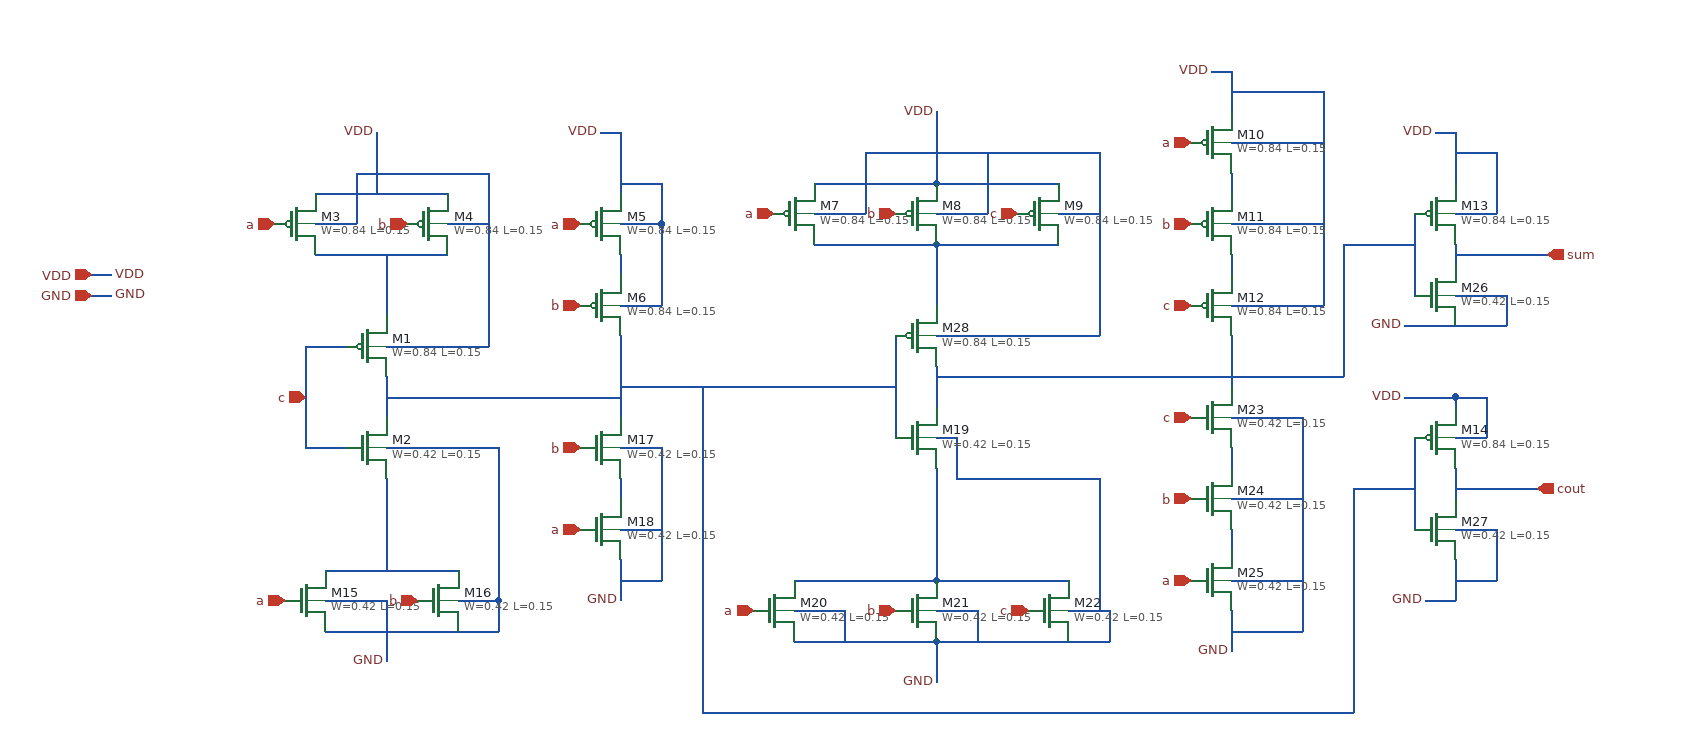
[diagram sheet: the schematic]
v {xschem version=3.4.3 file_version=1.2
}
G {}
K {}
V {}
S {}
E {}
N 210 -180 210 -140 {
lab=#net1}
N 130 -210 170 -210 {
lab=#net2}
N 130 -210 130 -110 {
lab=#net2}
N 130 -110 170 -110 {
lab=#net2}
N 210 -80 210 -60 {
lab=#net3}
N 210 -210 230 -210 {
lab=VDD}
N 210 -110 230 -110 {
lab=GND}
N 210 -60 210 -20 {
lab=#net3}
N -80 -280 -60 -280 {
lab=VDD}
N -80 -260 -60 -260 {
lab=GND}
N 140 -360 140 -350 {
lab=VDD}
N 140 -360 270 -360 {
lab=VDD}
N 200 -420 200 -360 {
lab=VDD}
N 420 -420 440 -420 {
lab=VDD}
N 440 -420 440 -360 {
lab=VDD}
N 750 -440 750 -370 {
lab=VDD}
N 630 -370 750 -370 {
lab=VDD}
N 750 -370 870 -370 {
lab=VDD}
N 1020 -480 1040 -480 {
lab=VDD}
N 1040 -480 1040 -440 {
lab=VDD}
N 1240 -420 1260 -420 {
lab=VDD}
N 1260 -420 1260 -370 {
lab=VDD}
N 1260 -310 1260 -290 {
lab=sum}
N 1040 -380 1040 -360 {
lab=#net4}
N 1040 -300 1040 -280 {
lab=#net5}
N 1260 -90 1260 -60 {
lab=cout}
N 1220 -120 1220 -30 {
lab=#net6}
N 1220 -340 1220 -260 {
lab=#net7}
N 1210 -230 1260 -230 {
lab=GND}
N 1260 -160 1260 -150 {
lab=VDD}
N 1210 -160 1260 -160 {
lab=VDD}
N 1260 0 1260 40 {
lab=GND}
N 1230 40 1260 40 {
lab=GND}
N 1040 -30 1040 -10 {
lab=#net8}
N 1040 -110 1040 -90 {
lab=#net9}
N 1040 50 1040 90 {
lab=GND}
N 750 80 880 80 {
lab=GND}
N 610 80 750 80 {
lab=GND}
N 750 80 750 120 {
lab=GND}
N 620 20 750 20 {
lab=#net10}
N 610 20 620 20 {
lab=#net10}
N 760 20 880 20 {
lab=#net10}
N 750 20 760 20 {
lab=#net10}
N 750 -90 750 20 {
lab=#net10}
N 750 -190 750 -150 {
lab=#net11}
N 750 -310 750 -250 {
lab=#net12}
N 630 -310 750 -310 {
lab=#net12}
N 750 -310 870 -310 {
lab=#net12}
N 1040 -220 1040 -170 {
lab=#net13}
N 440 -80 440 -60 {
lab=#net14}
N 440 -220 440 -140 {
lab=#net15}
N 440 0 440 40 {
lab=GND}
N 440 -300 440 -280 {
lab=#net16}
N 150 10 280 10 {
lab=#net3}
N 150 70 280 70 {
lab=GND}
N 210 70 210 100 {
lab=GND}
N 210 -20 210 10 {
lab=#net3}
N 210 -250 210 -240 {
lab=#net17}
N 150 -300 270 -300 {
lab=#net17}
N 140 -300 150 -300 {
lab=#net17}
N 210 -300 210 -250 {
lab=#net17}
N 440 -330 480 -330 {
lab=VDD}
N 480 -370 480 -330 {
lab=VDD}
N 440 -370 480 -370 {
lab=VDD}
N 460 -250 480 -250 {
lab=VDD}
N 440 -250 460 -250 {
lab=VDD}
N 480 -280 480 -250 {
lab=VDD}
N 480 -330 480 -290 {
lab=VDD}
N 480 -290 480 -280 {
lab=VDD}
N 440 -110 480 -110 {
lab=GND}
N 480 -110 480 20 {
lab=GND}
N 440 20 480 20 {
lab=GND}
N 440 -30 480 -30 {
lab=GND}
N 150 40 210 40 {
lab=GND}
N 210 40 210 70 {
lab=GND}
N 280 40 320 40 {
lab=GND}
N 320 50 320 70 {
lab=GND}
N 280 70 320 70 {
lab=GND}
N 320 40 320 50 {
lab=GND}
N 610 50 660 50 {
lab=GND}
N 660 50 660 80 {
lab=GND}
N 750 50 790 50 {
lab=GND}
N 790 50 790 80 {
lab=GND}
N 880 50 920 50 {
lab=GND}
N 920 60 920 80 {
lab=GND}
N 880 80 920 80 {
lab=GND}
N 920 50 920 60 {
lab=GND}
N 750 -120 770 -120 {
lab=GND}
N 770 -120 770 -80 {
lab=GND}
N 750 -220 910 -220 {
lab=VDD}
N 910 -400 910 -220 {
lab=VDD}
N 750 -400 910 -400 {
lab=VDD}
N 770 -80 910 -80 {
lab=GND}
N 910 -80 910 50 {
lab=GND}
N 880 -340 910 -340 {
lab=VDD}
N 870 -340 880 -340 {
lab=VDD}
N 750 -340 800 -340 {
lab=VDD}
N 800 -400 800 -340 {
lab=VDD}
N 630 -340 680 -340 {
lab=VDD}
N 680 -400 680 -340 {
lab=VDD}
N 680 -400 750 -400 {
lab=VDD}
N 1040 -250 1130 -250 {
lab=VDD}
N 1130 -460 1130 -250 {
lab=VDD}
N 1040 -460 1130 -460 {
lab=VDD}
N 1040 -410 1130 -410 {
lab=VDD}
N 1040 -330 1130 -330 {
lab=VDD}
N 1040 -140 1110 -140 {
lab=GND}
N 1110 -140 1110 70 {
lab=GND}
N 1040 70 1110 70 {
lab=GND}
N 1040 20 1110 20 {
lab=GND}
N 1040 -60 1110 -60 {
lab=GND}
N 1260 -120 1290 -120 {
lab=VDD}
N 1290 -160 1290 -120 {
lab=VDD}
N 1260 -160 1290 -160 {
lab=VDD}
N 1270 -30 1300 -30 {
lab=GND}
N 1300 -30 1300 20 {
lab=GND}
N 1260 20 1300 20 {
lab=GND}
N 1260 -30 1270 -30 {
lab=GND}
N 1260 -260 1310 -260 {
lab=GND}
N 1310 -260 1310 -230 {
lab=GND}
N 1260 -230 1310 -230 {
lab=GND}
N 1260 -340 1300 -340 {
lab=VDD}
N 1300 -400 1300 -340 {
lab=VDD}
N 1260 -400 1300 -400 {
lab=VDD}
N 1260 -70 1340 -70 {
lab=cout}
N 1260 -300 1350 -300 {
lab=sum}
N 230 -110 310 -110 {
lab=GND}
N 320 -100 320 40 {
lab=GND}
N 310 -110 320 -110 {
lab=GND}
N 320 -110 320 -100 {
lab=GND}
N 230 -210 310 -210 {
lab=VDD}
N 310 -360 310 -210 {
lab=VDD}
N 310 -380 310 -360 {
lab=VDD}
N 200 -380 300 -380 {
lab=VDD}
N 300 -380 310 -380 {
lab=VDD}
N 270 -330 310 -330 {
lab=VDD}
N 150 -330 180 -330 {
lab=VDD}
N 180 -380 180 -330 {
lab=VDD}
N 180 -380 200 -380 {
lab=VDD}
N 140 -330 150 -330 {
lab=VDD}
N 210 -160 440 -160 {}
N 710 -220 710 -120 {}
N 440 -170 710 -170 {}
N 750 -180 1040 -180 {}
N 1040 -180 1150 -180 {}
N 1150 -310 1150 -180 {}
N 1150 -310 1220 -310 {}
N 520 -170 520 150 {}
N 520 150 1160 150 {}
N 1160 -70 1160 150 {}
N 1160 -70 1220 -70 {}
C {devices/ipin.sym} 130 -160 0 0 {name=p2 lab=c
}
C {sky130_fd_pr/pfet_01v8.sym} 190 -210 0 0 {name=M1
L=0.15
W=0.84
nf=1
mult=1
ad="'int((nf+1)/2) * W/nf * 0.29'" 
pd="'2*int((nf+1)/2) * (W/nf + 0.29)'"
as="'int((nf+2)/2) * W/nf * 0.29'" 
ps="'2*int((nf+2)/2) * (W/nf + 0.29)'"
nrd="'0.29 / W'" nrs="'0.29 / W'"
sa=0 sb=0 sd=0
model=pfet_01v8
spiceprefix=X
}
C {sky130_fd_pr/nfet_01v8.sym} 190 -110 0 0 {name=M2
L=0.15
W=0.42
nf=1 
mult=1
ad="'int((nf+1)/2) * W/nf * 0.29'" 
pd="'2*int((nf+1)/2) * (W/nf + 0.29)'"
as="'int((nf+2)/2) * W/nf * 0.29'" 
ps="'2*int((nf+2)/2) * (W/nf + 0.29)'"
nrd="'0.29 / W'" nrs="'0.29 / W'"
sa=0 sb=0 sd=0
model=nfet_01v8
spiceprefix=X
}
C {devices/lab_pin.sym} 200 -420 0 0 {name=p3 sig_type=std_logic lab=VDD}
C {devices/lab_pin.sym} 210 100 0 0 {name=p4 sig_type=std_logic lab=GND}
C {devices/ipin.sym} -80 -280 0 0 {name=p5 lab=VDD}
C {devices/lab_pin.sym} -60 -280 0 1 {name=p6 sig_type=std_logic lab=VDD}
C {devices/ipin.sym} -80 -260 0 0 {name=p7 lab=GND}
C {devices/lab_pin.sym} -60 -260 0 1 {name=p8 sig_type=std_logic lab=GND}
C {sky130_fd_pr/pfet_01v8.sym} 120 -330 0 0 {name=M3
L=0.15
W=0.84
nf=1
mult=1
ad="'int((nf+1)/2) * W/nf * 0.29'" 
pd="'2*int((nf+1)/2) * (W/nf + 0.29)'"
as="'int((nf+2)/2) * W/nf * 0.29'" 
ps="'2*int((nf+2)/2) * (W/nf + 0.29)'"
nrd="'0.29 / W'" nrs="'0.29 / W'"
sa=0 sb=0 sd=0
model=pfet_01v8
spiceprefix=X
}
C {sky130_fd_pr/pfet_01v8.sym} 250 -330 0 0 {name=M4
L=0.15
W=0.84
nf=1
mult=1
ad="'int((nf+1)/2) * W/nf * 0.29'" 
pd="'2*int((nf+1)/2) * (W/nf + 0.29)'"
as="'int((nf+2)/2) * W/nf * 0.29'" 
ps="'2*int((nf+2)/2) * (W/nf + 0.29)'"
nrd="'0.29 / W'" nrs="'0.29 / W'"
sa=0 sb=0 sd=0
model=pfet_01v8
spiceprefix=X
}
C {sky130_fd_pr/pfet_01v8.sym} 420 -330 0 0 {name=M5
L=0.15
W=0.84
nf=1
mult=1
ad="'int((nf+1)/2) * W/nf * 0.29'" 
pd="'2*int((nf+1)/2) * (W/nf + 0.29)'"
as="'int((nf+2)/2) * W/nf * 0.29'" 
ps="'2*int((nf+2)/2) * (W/nf + 0.29)'"
nrd="'0.29 / W'" nrs="'0.29 / W'"
sa=0 sb=0 sd=0
model=pfet_01v8
spiceprefix=X
}
C {sky130_fd_pr/pfet_01v8.sym} 420 -250 0 0 {name=M6
L=0.15
W=0.84
nf=1
mult=1
ad="'int((nf+1)/2) * W/nf * 0.29'" 
pd="'2*int((nf+1)/2) * (W/nf + 0.29)'"
as="'int((nf+2)/2) * W/nf * 0.29'" 
ps="'2*int((nf+2)/2) * (W/nf + 0.29)'"
nrd="'0.29 / W'" nrs="'0.29 / W'"
sa=0 sb=0 sd=0
model=pfet_01v8
spiceprefix=X
}
C {sky130_fd_pr/pfet_01v8.sym} 610 -340 0 0 {name=M7
L=0.15
W=0.84
nf=1
mult=1
ad="'int((nf+1)/2) * W/nf * 0.29'" 
pd="'2*int((nf+1)/2) * (W/nf + 0.29)'"
as="'int((nf+2)/2) * W/nf * 0.29'" 
ps="'2*int((nf+2)/2) * (W/nf + 0.29)'"
nrd="'0.29 / W'" nrs="'0.29 / W'"
sa=0 sb=0 sd=0
model=pfet_01v8
spiceprefix=X
}
C {sky130_fd_pr/pfet_01v8.sym} 730 -340 0 0 {name=M8
L=0.15
W=0.84
nf=1
mult=1
ad="'int((nf+1)/2) * W/nf * 0.29'" 
pd="'2*int((nf+1)/2) * (W/nf + 0.29)'"
as="'int((nf+2)/2) * W/nf * 0.29'" 
ps="'2*int((nf+2)/2) * (W/nf + 0.29)'"
nrd="'0.29 / W'" nrs="'0.29 / W'"
sa=0 sb=0 sd=0
model=pfet_01v8
spiceprefix=X
}
C {sky130_fd_pr/pfet_01v8.sym} 850 -340 0 0 {name=M9
L=0.15
W=0.84
nf=1
mult=1
ad="'int((nf+1)/2) * W/nf * 0.29'" 
pd="'2*int((nf+1)/2) * (W/nf + 0.29)'"
as="'int((nf+2)/2) * W/nf * 0.29'" 
ps="'2*int((nf+2)/2) * (W/nf + 0.29)'"
nrd="'0.29 / W'" nrs="'0.29 / W'"
sa=0 sb=0 sd=0
model=pfet_01v8
spiceprefix=X
}
C {sky130_fd_pr/pfet_01v8.sym} 1020 -410 0 0 {name=M10
L=0.15
W=0.84
nf=1
mult=1
ad="'int((nf+1)/2) * W/nf * 0.29'" 
pd="'2*int((nf+1)/2) * (W/nf + 0.29)'"
as="'int((nf+2)/2) * W/nf * 0.29'" 
ps="'2*int((nf+2)/2) * (W/nf + 0.29)'"
nrd="'0.29 / W'" nrs="'0.29 / W'"
sa=0 sb=0 sd=0
model=pfet_01v8
spiceprefix=X
}
C {sky130_fd_pr/pfet_01v8.sym} 1020 -330 0 0 {name=M11
L=0.15
W=0.84
nf=1
mult=1
ad="'int((nf+1)/2) * W/nf * 0.29'" 
pd="'2*int((nf+1)/2) * (W/nf + 0.29)'"
as="'int((nf+2)/2) * W/nf * 0.29'" 
ps="'2*int((nf+2)/2) * (W/nf + 0.29)'"
nrd="'0.29 / W'" nrs="'0.29 / W'"
sa=0 sb=0 sd=0
model=pfet_01v8
spiceprefix=X
}
C {sky130_fd_pr/pfet_01v8.sym} 1020 -250 0 0 {name=M12
L=0.15
W=0.84
nf=1
mult=1
ad="'int((nf+1)/2) * W/nf * 0.29'" 
pd="'2*int((nf+1)/2) * (W/nf + 0.29)'"
as="'int((nf+2)/2) * W/nf * 0.29'" 
ps="'2*int((nf+2)/2) * (W/nf + 0.29)'"
nrd="'0.29 / W'" nrs="'0.29 / W'"
sa=0 sb=0 sd=0
model=pfet_01v8
spiceprefix=X
}
C {sky130_fd_pr/pfet_01v8.sym} 1240 -340 0 0 {name=M13
L=0.15
W=0.84
nf=1
mult=1
ad="'int((nf+1)/2) * W/nf * 0.29'" 
pd="'2*int((nf+1)/2) * (W/nf + 0.29)'"
as="'int((nf+2)/2) * W/nf * 0.29'" 
ps="'2*int((nf+2)/2) * (W/nf + 0.29)'"
nrd="'0.29 / W'" nrs="'0.29 / W'"
sa=0 sb=0 sd=0
model=pfet_01v8
spiceprefix=X
}
C {sky130_fd_pr/pfet_01v8.sym} 1240 -120 0 0 {name=M14
L=0.15
W=0.84
nf=1
mult=1
ad="'int((nf+1)/2) * W/nf * 0.29'" 
pd="'2*int((nf+1)/2) * (W/nf + 0.29)'"
as="'int((nf+2)/2) * W/nf * 0.29'" 
ps="'2*int((nf+2)/2) * (W/nf + 0.29)'"
nrd="'0.29 / W'" nrs="'0.29 / W'"
sa=0 sb=0 sd=0
model=pfet_01v8
spiceprefix=X
}
C {sky130_fd_pr/nfet_01v8.sym} 130 40 0 0 {name=M15
L=0.15
W=0.42
nf=1 
mult=1
ad="'int((nf+1)/2) * W/nf * 0.29'" 
pd="'2*int((nf+1)/2) * (W/nf + 0.29)'"
as="'int((nf+2)/2) * W/nf * 0.29'" 
ps="'2*int((nf+2)/2) * (W/nf + 0.29)'"
nrd="'0.29 / W'" nrs="'0.29 / W'"
sa=0 sb=0 sd=0
model=nfet_01v8
spiceprefix=X
}
C {sky130_fd_pr/nfet_01v8.sym} 260 40 0 0 {name=M16
L=0.15
W=0.42
nf=1 
mult=1
ad="'int((nf+1)/2) * W/nf * 0.29'" 
pd="'2*int((nf+1)/2) * (W/nf + 0.29)'"
as="'int((nf+2)/2) * W/nf * 0.29'" 
ps="'2*int((nf+2)/2) * (W/nf + 0.29)'"
nrd="'0.29 / W'" nrs="'0.29 / W'"
sa=0 sb=0 sd=0
model=nfet_01v8
spiceprefix=X
}
C {sky130_fd_pr/nfet_01v8.sym} 420 -110 0 0 {name=M17
L=0.15
W=0.42
nf=1 
mult=1
ad="'int((nf+1)/2) * W/nf * 0.29'" 
pd="'2*int((nf+1)/2) * (W/nf + 0.29)'"
as="'int((nf+2)/2) * W/nf * 0.29'" 
ps="'2*int((nf+2)/2) * (W/nf + 0.29)'"
nrd="'0.29 / W'" nrs="'0.29 / W'"
sa=0 sb=0 sd=0
model=nfet_01v8
spiceprefix=X
}
C {sky130_fd_pr/nfet_01v8.sym} 420 -30 0 0 {name=M18
L=0.15
W=0.42
nf=1 
mult=1
ad="'int((nf+1)/2) * W/nf * 0.29'" 
pd="'2*int((nf+1)/2) * (W/nf + 0.29)'"
as="'int((nf+2)/2) * W/nf * 0.29'" 
ps="'2*int((nf+2)/2) * (W/nf + 0.29)'"
nrd="'0.29 / W'" nrs="'0.29 / W'"
sa=0 sb=0 sd=0
model=nfet_01v8
spiceprefix=X
}
C {sky130_fd_pr/nfet_01v8.sym} 730 -120 0 0 {name=M19
L=0.15
W=0.42
nf=1 
mult=1
ad="'int((nf+1)/2) * W/nf * 0.29'" 
pd="'2*int((nf+1)/2) * (W/nf + 0.29)'"
as="'int((nf+2)/2) * W/nf * 0.29'" 
ps="'2*int((nf+2)/2) * (W/nf + 0.29)'"
nrd="'0.29 / W'" nrs="'0.29 / W'"
sa=0 sb=0 sd=0
model=nfet_01v8
spiceprefix=X
}
C {sky130_fd_pr/nfet_01v8.sym} 590 50 0 0 {name=M20
L=0.15
W=0.42
nf=1 
mult=1
ad="'int((nf+1)/2) * W/nf * 0.29'" 
pd="'2*int((nf+1)/2) * (W/nf + 0.29)'"
as="'int((nf+2)/2) * W/nf * 0.29'" 
ps="'2*int((nf+2)/2) * (W/nf + 0.29)'"
nrd="'0.29 / W'" nrs="'0.29 / W'"
sa=0 sb=0 sd=0
model=nfet_01v8
spiceprefix=X
}
C {sky130_fd_pr/nfet_01v8.sym} 730 50 0 0 {name=M21
L=0.15
W=0.42
nf=1 
mult=1
ad="'int((nf+1)/2) * W/nf * 0.29'" 
pd="'2*int((nf+1)/2) * (W/nf + 0.29)'"
as="'int((nf+2)/2) * W/nf * 0.29'" 
ps="'2*int((nf+2)/2) * (W/nf + 0.29)'"
nrd="'0.29 / W'" nrs="'0.29 / W'"
sa=0 sb=0 sd=0
model=nfet_01v8
spiceprefix=X
}
C {sky130_fd_pr/nfet_01v8.sym} 860 50 0 0 {name=M22
L=0.15
W=0.42
nf=1 
mult=1
ad="'int((nf+1)/2) * W/nf * 0.29'" 
pd="'2*int((nf+1)/2) * (W/nf + 0.29)'"
as="'int((nf+2)/2) * W/nf * 0.29'" 
ps="'2*int((nf+2)/2) * (W/nf + 0.29)'"
nrd="'0.29 / W'" nrs="'0.29 / W'"
sa=0 sb=0 sd=0
model=nfet_01v8
spiceprefix=X
}
C {sky130_fd_pr/nfet_01v8.sym} 1020 -140 0 0 {name=M23
L=0.15
W=0.42
nf=1 
mult=1
ad="'int((nf+1)/2) * W/nf * 0.29'" 
pd="'2*int((nf+1)/2) * (W/nf + 0.29)'"
as="'int((nf+2)/2) * W/nf * 0.29'" 
ps="'2*int((nf+2)/2) * (W/nf + 0.29)'"
nrd="'0.29 / W'" nrs="'0.29 / W'"
sa=0 sb=0 sd=0
model=nfet_01v8
spiceprefix=X
}
C {sky130_fd_pr/nfet_01v8.sym} 1020 -60 0 0 {name=M24
L=0.15
W=0.42
nf=1 
mult=1
ad="'int((nf+1)/2) * W/nf * 0.29'" 
pd="'2*int((nf+1)/2) * (W/nf + 0.29)'"
as="'int((nf+2)/2) * W/nf * 0.29'" 
ps="'2*int((nf+2)/2) * (W/nf + 0.29)'"
nrd="'0.29 / W'" nrs="'0.29 / W'"
sa=0 sb=0 sd=0
model=nfet_01v8
spiceprefix=X
}
C {sky130_fd_pr/nfet_01v8.sym} 1020 20 0 0 {name=M25
L=0.15
W=0.42
nf=1 
mult=1
ad="'int((nf+1)/2) * W/nf * 0.29'" 
pd="'2*int((nf+1)/2) * (W/nf + 0.29)'"
as="'int((nf+2)/2) * W/nf * 0.29'" 
ps="'2*int((nf+2)/2) * (W/nf + 0.29)'"
nrd="'0.29 / W'" nrs="'0.29 / W'"
sa=0 sb=0 sd=0
model=nfet_01v8
spiceprefix=X
}
C {sky130_fd_pr/nfet_01v8.sym} 1240 -260 0 0 {name=M26
L=0.15
W=0.42
nf=1 
mult=1
ad="'int((nf+1)/2) * W/nf * 0.29'" 
pd="'2*int((nf+1)/2) * (W/nf + 0.29)'"
as="'int((nf+2)/2) * W/nf * 0.29'" 
ps="'2*int((nf+2)/2) * (W/nf + 0.29)'"
nrd="'0.29 / W'" nrs="'0.29 / W'"
sa=0 sb=0 sd=0
model=nfet_01v8
spiceprefix=X
}
C {sky130_fd_pr/nfet_01v8.sym} 1240 -30 0 0 {name=M27
L=0.15
W=0.42
nf=1 
mult=1
ad="'int((nf+1)/2) * W/nf * 0.29'" 
pd="'2*int((nf+1)/2) * (W/nf + 0.29)'"
as="'int((nf+2)/2) * W/nf * 0.29'" 
ps="'2*int((nf+2)/2) * (W/nf + 0.29)'"
nrd="'0.29 / W'" nrs="'0.29 / W'"
sa=0 sb=0 sd=0
model=nfet_01v8
spiceprefix=X
}
C {sky130_fd_pr/pfet_01v8.sym} 730 -220 0 0 {name=M28
L=0.15
W=0.84
nf=1
mult=1
ad="'int((nf+1)/2) * W/nf * 0.29'" 
pd="'2*int((nf+1)/2) * (W/nf + 0.29)'"
as="'int((nf+2)/2) * W/nf * 0.29'" 
ps="'2*int((nf+2)/2) * (W/nf + 0.29)'"
nrd="'0.29 / W'" nrs="'0.29 / W'"
sa=0 sb=0 sd=0
model=pfet_01v8
spiceprefix=X
}
C {devices/lab_pin.sym} 440 40 0 0 {name=p9 sig_type=std_logic lab=GND}
C {devices/lab_pin.sym} 750 120 0 0 {name=p10 sig_type=std_logic lab=GND}
C {devices/lab_pin.sym} 1040 90 0 0 {name=p11 sig_type=std_logic lab=GND}
C {devices/lab_pin.sym} 1230 40 0 0 {name=p12 sig_type=std_logic lab=GND}
C {devices/lab_pin.sym} 1210 -230 0 0 {name=p13 sig_type=std_logic lab=GND}
C {devices/lab_pin.sym} 420 -420 0 0 {name=p14 sig_type=std_logic lab=VDD}
C {devices/lab_pin.sym} 750 -440 0 0 {name=p15 sig_type=std_logic lab=VDD}
C {devices/lab_pin.sym} 1020 -480 0 0 {name=p16 sig_type=std_logic lab=VDD}
C {devices/lab_pin.sym} 1240 -420 0 0 {name=p17 sig_type=std_logic lab=VDD}
C {devices/lab_pin.sym} 1210 -160 0 0 {name=p18 sig_type=std_logic lab=VDD}
C {devices/opin.sym} 1340 -70 0 0 {name=p19 lab=cout}
C {devices/opin.sym} 1350 -300 0 0 {name=p20 lab=sum}
C {devices/ipin.sym} 100 -330 0 0 {name=p1 lab=a}
C {devices/ipin.sym} 400 -330 0 0 {name=p21 lab=a}
C {devices/ipin.sym} 110 40 0 0 {name=p22 lab=a}
C {devices/ipin.sym} 400 -30 0 0 {name=p23 lab=a}
C {devices/ipin.sym} 590 -340 0 0 {name=p24 lab=a}
C {devices/ipin.sym} 570 50 0 0 {name=p25 lab=a}
C {devices/ipin.sym} 1000 -410 0 0 {name=p26 lab=a}
C {devices/ipin.sym} 1000 20 0 0 {name=p27 lab=a}
C {devices/ipin.sym} 230 -330 0 0 {name=p28 lab=b}
C {devices/ipin.sym} 240 40 0 0 {name=p29 lab=b}
C {devices/ipin.sym} 400 -110 0 0 {name=p30 lab=b}
C {devices/ipin.sym} 400 -250 0 0 {name=p31 lab=b}
C {devices/ipin.sym} 710 -340 0 0 {name=p32 lab=b}
C {devices/ipin.sym} 710 50 0 0 {name=p33 lab=b}
C {devices/ipin.sym} 1000 -60 0 0 {name=p34 lab=b}
C {devices/ipin.sym} 1000 -330 0 0 {name=p35 lab=b}
C {devices/ipin.sym} 830 -340 0 0 {name=p36 lab=c
}
C {devices/ipin.sym} 840 50 0 0 {name=p37 lab=c
}
C {devices/ipin.sym} 1000 -140 0 0 {name=p38 lab=c
}
C {devices/ipin.sym} 1000 -250 0 0 {name=p39 lab=c
}
